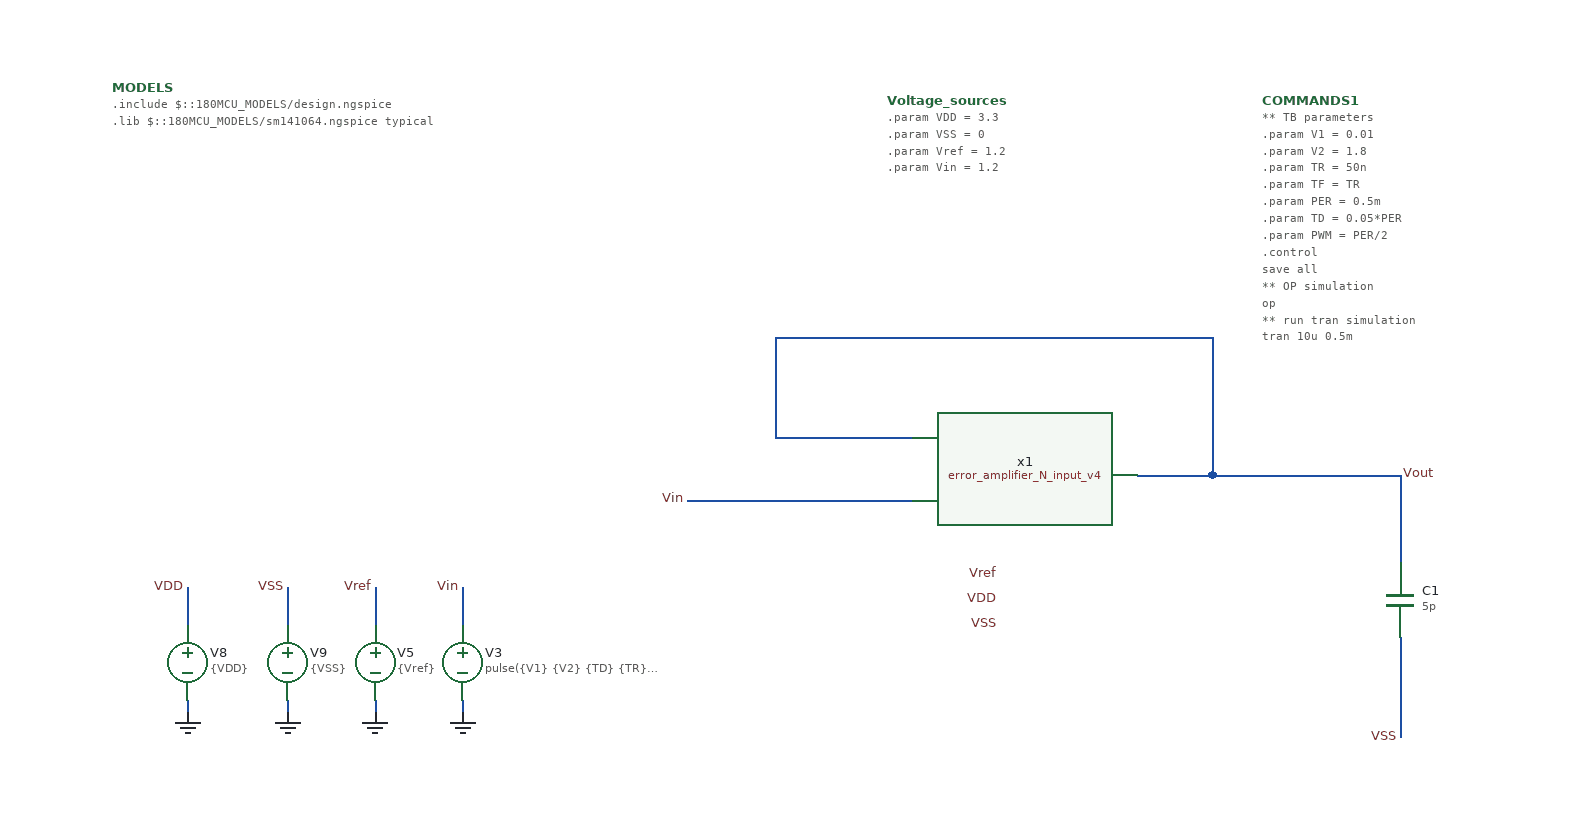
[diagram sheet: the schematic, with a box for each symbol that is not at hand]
v {xschem version=3.4.7 file_version=1.2}
G {}
K {}
V {}
S {}
E {}
N 890 -280 950 -280 {lab=Vout}
N 1100 -150 1100 -70 {
lab=VSS}
N 1100 -280 1100 -220 {
lab=Vout}
N 950 -280 1100 -280 {
lab=Vout}
N 530 -260 710 -260 {
lab=Vin}
N 1100 -220 1100 -210 {
lab=Vout}
N 600 -310 710 -310 {
lab=Vout}
N 600 -390 600 -310 {
lab=Vout}
N 600 -390 950 -390 {
lab=Vout}
N 950 -390 950 -280 {
lab=Vout}
N 350 -100 350 -90 {lab=GND}
N 350 -190 350 -160 {lab=Vin}
N 130 -100 130 -90 {lab=GND}
N 130 -190 130 -160 {lab=VDD}
N 210 -100 210 -90 {lab=GND}
N 210 -190 210 -160 {lab=VSS}
N 280 -100 280 -90 {lab=GND}
N 280 -190 280 -160 {lab=Vref}
C {lab_pin.sym} 780 -200 2 1 {name=p7 sig_type=std_logic lab=Vref}
C {lab_pin.sym} 780 -180 2 1 {name=p8 sig_type=std_logic lab=VDD}
C {lab_pin.sym} 780 -160 2 1 {name=p9 sig_type=std_logic lab=VSS}
C {lab_pin.sym} 530 -260 2 1 {name=p10 sig_type=std_logic lab=Vin}
C {capa.sym} 1100 -180 0 0 {name=C1
m=1
value=5p
footprint=1206
device="ceramic capacitor"}
C {lab_pin.sym} 1100 -70 2 1 {name=p1 sig_type=std_logic lab=VSS}
C {noconn.sym} 820 -220 2 0 {name=l1}
C {lab_pin.sym} 1100 -280 0 1 {name=p2 sig_type=std_logic lab=Vout}
C {vsource.sym} 350 -130 0 0 {name=V3 value="pulse(\{V1\} \{V2\} \{TD\} \{TR\} \{TF\} \{PWM\} \{PER\})" savecurrent=false
*pulse(0.01 1.8 \{TD\} \{TR\} \{TF\} \{PWM\} \{PER\})
*sin(0.9 0.8 1k)}
C {devices/code_shown.sym} 70 -590 0 0 {name=MODELS only_toplevel=true
format="tcleval( @value )"
value="
.include $::180MCU_MODELS/design.ngspice
.lib $::180MCU_MODELS/sm141064.ngspice typical
"}
C {devices/gnd.sym} 350 -90 0 0 {name=l8 lab=GND}
C {devices/lab_wire.sym} 350 -190 0 0 {name=p14 sig_type=std_logic lab=Vin}
C {devices/code_shown.sym} 690 -580 0 0 {name=Voltage_sources only_toplevel=true
value="
.param VDD = 3.3
.param VSS = 0
.param Vref = 1.2
.param Vin = 1.2
"}
C {devices/vsource.sym} 130 -130 0 0 {name=V8 value=\{VDD\}}
C {devices/gnd.sym} 130 -90 0 0 {name=l12 lab=GND}
C {devices/lab_wire.sym} 130 -190 0 0 {name=p19 sig_type=std_logic lab=VDD}
C {devices/vsource.sym} 210 -130 0 0 {name=V9 value=\{VSS\}}
C {devices/gnd.sym} 210 -90 0 0 {name=l13 lab=GND}
C {devices/lab_wire.sym} 210 -190 0 0 {name=p20 sig_type=std_logic lab=VSS}
C {simulator_commands.sym} 990 -580 0 0 {name=COMMANDS1
simulator=ngspice
only_toplevel=false 
value="
** TB parameters
.param V1 = 0.01
.param V2 = 1.8
.param TR = 50n
.param TF = TR
.param PER = 0.5m
.param TD = 0.05*PER
.param PWM = PER/2

.control
save all

** OP simulation
op

** run tran simulation
tran 10u 0.5m

** All OP parameters
setplot op1

let #####_M1_nmos_input_##### = 0 
let id_M1 = @m.x1.x1.xm1.m0[id]
let gm_M1 = @m.x1.x1.xm1.m0[gm]
let ro_M1 = 1/@m.x1.x1.xm1.m0[gds]
let Vgs_M1 = @m.x1.x1.xm1.m0[vgs]
let Vds_M1 = @m.x1.x1.xm1.m0[vds]
let Vsb_M1 = -@m.x1.x1.xm1.m0[vbs]
let Vdsat_M1 = @m.x1.x1.xm1.m0[vdsat]
let Vth_M1 = @m.x1.x1.xm1.m0[vth]
let ao_M1 = gm_M1*ro_M1
let gmid_M1 = gm_M1/id_M1
let fT_M1 = gm_M1/(6.283185*@m.x1.x1.xm1.m0[cgg])
print #####_M1_nmos_input_##### id_M1 gm_M1 ro_M1 Vgs_M1 Vds_M1 Vsb_M1 Vdsat_M1 Vth_M1 ao_M1 gmid_M1 fT_M1

let #####_M2_nmos_input_##### = 0 
let id_M2 = @m.x1.x1.xm2.m0[id]
let gm_M2 = @m.x1.x1.xm2.m0[gm]
let ro_M2 = 1/@m.x1.x1.xm2.m0[gds]
let Vgs_M2 = @m.x1.x1.xm2.m0[vgs]
let Vds_M2 = @m.x1.x1.xm2.m0[vds]
let Vsb_M2 = -@m.x1.x1.xm2.m0[vbs]
let Vdsat_M2 = @m.x1.x1.xm2.m0[vdsat]
let Vth_M2 = @m.x1.x1.xm2.m0[vth]
let ao_M2 = gm_M2*ro_M2
let gmid_M2 = gm_M2/id_M2
let fT_M2 = gm_M2/(6.283185*@m.x1.x1.xm2.m0[cgg])
print #####_M2_nmos_input_##### id_M2 gm_M2 ro_M2 Vgs_M2 Vds_M2 Vsb_M2 Vdsat_M2 Vth_M2 ao_M2 gmid_M2 fT_M2

let #####_M3_pmos_top_##### = 0 
let id_M3 = @m.x1.x1.xm3.m0[id]
let gm_M3 = @m.x1.x1.xm3.m0[gm]
let ro_M3 = 1/@m.x1.x1.xm3.m0[gds]
let Vsg_M3 = @m.x1.x1.xm3.m0[vgs]
let Vsd_M3 = @m.x1.x1.xm3.m0[vds]
let Vbs_M3 = -@m.x1.x1.xm3.m0[vbs]
let Vdsat_M3 = @m.x1.x1.xm3.m0[vdsat]
let Vth_M3 = @m.x1.x1.xm3.m0[vth]
let ao_M3 = gm_M3*ro_M3
let gmid_M3 = gm_M3/id_M3
let fT_M3 = gm_M3/(6.283185*@m.x1.x1.xm3.m0[cgg])
print #####_M3_pmos_top_##### id_M3 gm_M3 ro_M3 Vsg_M3 Vsd_M3 Vbs_M3 Vdsat_M3 Vth_M3 ao_M3 gmid_M3 fT_M3

let #####_M4_pmos_top_##### = 0 
let id_M4 = @m.x1.x1.xm4.m0[id]
let gm_M4 = @m.x1.x1.xm4.m0[gm]
let ro_M4 = 1/@m.x1.x1.xm4.m0[gds]
let Vsg_M4 = @m.x1.x1.xm4.m0[vgs]
let Vsd_M4 = @m.x1.x1.xm4.m0[vds]
let Vbs_M4 = -@m.x1.x1.xm4.m0[vbs]
let Vdsat_M4 = @m.x1.x1.xm4.m0[vdsat]
let Vth_M4 = @m.x1.x1.xm4.m0[vth]
let ao_M4 = gm_M4*ro_M4
let gmid_M4 = gm_M4/id_M4
let fT_M4 = gm_M4/(6.283185*@m.x1.x1.xm4.m0[cgg])
print #####_M4_pmos_top_##### id_M4 gm_M4 ro_M4 Vsg_M4 Vsd_M4 Vbs_M4 Vdsat_M4 Vth_M4 ao_M4 gmid_M4 fT_M4

let #####_M5_pmos_out_##### = 0 
let id_M5 = @m.x1.x1.xm5.m0[id]
let gm_M5 = @m.x1.x1.xm5.m0[gm]
let ro_M5 = 1/@m.x1.x1.xm5.m0[gds]
let Vsg_M5 = @m.x1.x1.xm5.m0[vgs]
let Vsd_M5 = @m.x1.x1.xm5.m0[vds]
let Vbs_M5 = -@m.x1.x1.xm5.m0[vbs]
let Vdsat_M5 = @m.x1.x1.xm5.m0[vdsat]
let Vth_M5 = @m.x1.x1.xm5.m0[vth]
let ao_M5 = gm_M5*ro_M5
let gmid_M5 = gm_M5/id_M5
let fT_M5 = gm_M5/(6.283185*@m.x1.x1.xm5.m0[cgg])
print #####_M5_pmos_out_##### id_M5 gm_M5 ro_M5 Vsg_M5 Vsd_M5 Vbs_M5 Vdsat_M5 Vth_M5 ao_M5 gmid_M5 fT_M5

let #####_M6_pmos_out_##### = 0 
let id_M6 = @m.x1.x1.xm6.m0[id]
let gm_M6 = @m.x1.x1.xm6.m0[gm]
let ro_M6 = 1/@m.x1.x1.xm6.m0[gds]
let Vsg_M6 = @m.x1.x1.xm6.m0[vgs]
let Vsd_M6 = @m.x1.x1.xm6.m0[vds]
let Vbs_M6 = -@m.x1.x1.xm6.m0[vbs]
let Vdsat_M6 = @m.x1.x1.xm6.m0[vdsat]
let Vth_M6 = @m.x1.x1.xm6.m0[vth]
let ao_M6 = gm_M6*ro_M6
let gmid_M6 = gm_M6/id_M6
let fT_M6 = gm_M6/(6.283185*@m.x1.x1.xm6.m0[cgg])
print #####_M6_pmos_out_##### id_M6 gm_M6 ro_M6 Vsg_M6 Vsd_M6 Vbs_M6 Vdsat_M6 Vth_M6 ao_M6 gmid_M6 fT_M6

let #####_M7_nmos_out_##### = 0 
let id_M7 = @m.x1.x1.xm7.m0[id]
let gm_M7 = @m.x1.x1.xm7.m0[gm]
let ro_M7 = 1/@m.x1.x1.xm7.m0[gds]
let Vgs_M7 = @m.x1.x1.xm7.m0[vgs]
let Vds_M7 = @m.x1.x1.xm7.m0[vds]
let Vsb_M7 = -@m.x1.x1.xm7.m0[vbs]
let Vdsat_M7 = @m.x1.x1.xm7.m0[vdsat]
let Vth_M7 = @m.x1.x1.xm7.m0[vth]
let ao_M7 = gm_M7*ro_M7
let gmid_M7 = gm_M7/id_M7
let fT_M7 = gm_M7/(6.283185*@m.x1.x1.xm7.m0[cgg])
print #####_M7_nmos_out_##### id_M7 gm_M7 ro_M7 Vgs_M7 Vds_M7 Vsb_M7 Vdsat_M7 Vth_M7 ao_M7 gmid_M7 fT_M7

let #####_M8_nmos_out_##### = 0 
let id_M8 = @m.x1.x1.xm8.m0[id]
let gm_M8 = @m.x1.x1.xm8.m0[gm]
let ro_M8 = 1/@m.x1.x1.xm8.m0[gds]
let Vgs_M8 = @m.x1.x1.xm8.m0[vgs]
let Vds_M8 = @m.x1.x1.xm8.m0[vds]
let Vsb_M8 = -@m.x1.x1.xm8.m0[vbs]
let Vdsat_M8 = @m.x1.x1.xm8.m0[vdsat]
let Vth_M8 = @m.x1.x1.xm8.m0[vth]
let ao_M8 = gm_M8*ro_M8
let gmid_M8 = gm_M8/id_M8
let fT_M8 = gm_M8/(6.283185*@m.x1.x1.xm8.m0[cgg])
print #####_M8_nmos_out_##### id_M8 gm_M8 ro_M8 Vgs_M8 Vds_M8 Vsb_M8 Vdsat_M8 Vth_M8 ao_M8 gmid_M8 fT_M8

let #####_M9_nmos_bottom_##### = 0 
let id_M9 = @m.x1.x1.xm9.m0[id]
let gm_M9 = @m.x1.x1.xm9.m0[gm]
let ro_M9 = 1/@m.x1.x1.xm9.m0[gds]
let Vgs_M9 = @m.x1.x1.xm9.m0[vgs]
let Vds_M9 = @m.x1.x1.xm9.m0[vds]
let Vsb_M9 = -@m.x1.x1.xm9.m0[vbs]
let Vdsat_M9 = @m.x1.x1.xm9.m0[vdsat]
let Vth_M9 = @m.x1.x1.xm9.m0[vth]
let ao_M9 = gm_M9*ro_M9
let gmid_M9 = gm_M9/id_M9
let fT_M9 = gm_M9/(6.283185*@m.x1.x1.xm9.m0[cgg])
print #####_M9_nmos_bottom_##### id_M9 gm_M9 ro_M9 Vgs_M9 Vds_M9 Vsb_M9 Vdsat_M9 Vth_M9 ao_M9 gmid_M9 fT_M9

let #####_M10_nmos_bottom_##### = 0 
let id_M10 = @m.x1.x1.xm10.m0[id]
let gm_M10 = @m.x1.x1.xm10.m0[gm]
let ro_M10 = 1/@m.x1.x1.xm10.m0[gds]
let Vgs_M10 = @m.x1.x1.xm10.m0[vgs]
let Vds_M10 = @m.x1.x1.xm10.m0[vds]
let Vsb_M10 = @m.x1.x1.xm10.m0[vbs]
let Vdsat_M10 = @m.x1.x1.xm10.m0[vdsat]
let Vth_M10 = @m.x1.x1.xm10.m0[vth]
let ao_M10 = gm_M10*ro_M10
let gmid_M10 = gm_M10/id_M10
let fT_M10 = gm_M10/(6.283185*@m.x1.x1.xm10.m0[cgg])
print #####_M10_nmos_bottom_##### id_M10 gm_M10 ro_M10 Vgs_M10 Vds_M10 Vsb_M10 Vdsat_M10 Vth_M10 ao_M10 gmid_M10 fT_M10

let #####_M11_nmos_mirror_##### = 0 
let id_M11 = @m.x1.x1.xm11.m0[id]
let gm_M11 = @m.x1.x1.xm11.m0[gm]
let ro_M11 = 1/@m.x1.x1.xm11.m0[gds]
let Vgs_M11 = @m.x1.x1.xm11.m0[vgs]
let Vds_M11 = @m.x1.x1.xm11.m0[vds]
let Vsb_M11 = -@m.x1.x1.xm11.m0[vbs]
let Vdsat_M11 = @m.x1.x1.xm11.m0[vdsat]
let Vth_M11 = @m.x1.x1.xm11.m0[vth]
let ao_M11 = gm_M11*ro_M11
let gmid_M11 = gm_M11/id_M11
let fT_M11 = gm_M11/(6.283185*@m.x1.x1.xm11.m0[cgg])
print #####_M11_nmos_mirror_##### id_M11 gm_M11 ro_M11 Vgs_M11 Vds_M11 Vsb_M11 Vdsat_M11 Vth_M11 ao_M11 gmid_M11 fT_M11

** Custom output
let #####_Custom_output_##### = 0

* Power
let power = abs(i(V8))*VDD

* DC_gain
let r1 = ao_M6*ro_M4
let r2 = ao_M8*((ro_M1*ro_M10)/(ro_M1+ro_M10))
let Rout = (r1*r2)/(r1+r2)
let Av = db(gm_M1*Rout)
* Bandwidth 
let BW = 1/(Rout*1e-12*6.283185)

print #####_Custom_output_##### Av BW Rout power gm_M1 ro_M1 gm_M6 ro_M6 ro_M4 gm_M8 ro_M8 ro_M10

write error_amplifier_N_input_v4_TB_sr.raw

setplot tran1

* measure parameters
let dVout = deriv(Vout)/1e6
meas tran SRplus MAX dVout
meas tran SRminus MIN dVout

print SRplus SRminus

plot Vout Vin

.endc
"}
C {devices/vsource.sym} 280 -130 0 0 {name=V5 value=\{Vref\}}
C {devices/gnd.sym} 280 -90 0 0 {name=l10 lab=GND}
C {devices/lab_wire.sym} 280 -190 0 0 {name=p4 sig_type=std_logic lab=Vref}
C {gf180/error_amplifier_N_input_v4/xschem/error_amplifier_N_input_v4.sym} 800 -280 0 0 {name=x1}
C {devices/launcher.sym} 180 -420 0 0 {name=h3
descr="Save & Netlist & sim" 
tclcommand="xschem save; xschem netlist; xschem simulate"}
C {launcher.sym} 180 -360 0 0 {name=h2
descr="Annotate OP"
tclcommand="set show_hidden_texts 1; xschem annotate_op"}
